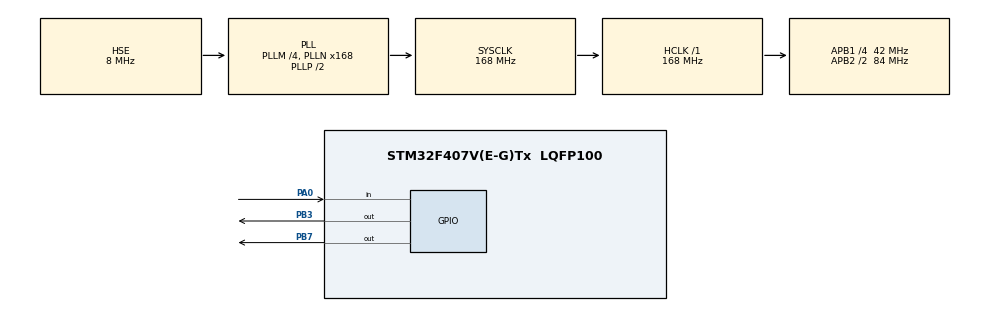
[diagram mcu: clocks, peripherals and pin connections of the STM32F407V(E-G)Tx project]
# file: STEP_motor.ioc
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Mcu.Family=STM32F4
Mcu.Name=STM32F407V(E-G)Tx
Mcu.Package=LQFP100
NVIC.PriorityGroup=NVIC_PRIORITYGROUP_4
PA0-WKUP.GPIO_PuPd=GPIO_PULLDOWN
PA0-WKUP.Signal=GPIO_Input
PA13.Mode=Serial_Wire
PA13.Signal=SYS_JTMS-SWDIO
PA14.Mode=Serial_Wire
PA14.Signal=SYS_JTCK-SWCLK
PB3.Signal=GPIO_Output
PB7.Signal=GPIO_Output
PH0-OSC_IN.Mode=HSE-External-Oscillator
PH0-OSC_IN.Signal=RCC_OSC_IN
PH1-OSC_OUT.Mode=HSE-External-Oscillator
PH1-OSC_OUT.Signal=RCC_OSC_OUT
ProjectManager.HeapSize=0x200
ProjectManager.StackSize=0x400
ProjectManager.TargetToolchain=MDK-ARM V5.27
RCC.48MHZClocksFreq_Value=84000000
RCC.AHBFreq_Value=168000000
RCC.APB1CLKDivider=RCC_HCLK_DIV4
RCC.APB1Freq_Value=42000000
RCC.APB1TimFreq_Value=84000000
RCC.APB2CLKDivider=RCC_HCLK_DIV2
RCC.APB2Freq_Value=84000000
RCC.APB2TimFreq_Value=168000000
RCC.CortexFreq_Value=168000000
RCC.HCLKFreq_Value=168000000
RCC.HSE_VALUE=8000000
RCC.HSI_VALUE=16000000
RCC.LSE_VALUE=32768
RCC.PLLM=4
RCC.PLLN=168
RCC.PLLSourceVirtual=RCC_PLLSOURCE_HSE
RCC.SYSCLKFreq_VALUE=168000000
RCC.SYSCLKSource=RCC_SYSCLKSOURCE_PLLCLK
RCC.VCOOutputFreq_Value=336000000
board=custom

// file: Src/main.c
/* USER CODE BEGIN Header */
/**
  ******************************************************************************
  * @file           : main.c
  * @brief          : Main program body
  ******************************************************************************
  * @attention
  *
  * <h2><center>&copy; Copyright (c) 2020 STMicroelectronics.
  * All rights reserved.</center></h2>
  *
  * This software component is licensed by ST under BSD 3-Clause license,
  * the "License"; You may not use this file except in compliance with the
  * License. You may obtain a copy of the License at:
  *                        opensource.org/licenses/BSD-3-Clause
  *
  ******************************************************************************
  */
/* USER CODE END Header */

#include "main.h"

void SystemClock_Config(void);
static void MX_GPIO_Init(void);

int main(void)
{

  /* MCU Configuration--------------------------------------------------------*/

  /* Reset of all peripherals, Initializes the Flash interface and the Systick. */
  HAL_Init();

  /* Configure the system clock */
  SystemClock_Config();

  /* Initialize all configured peripherals */
  MX_GPIO_Init();

  /* USER CODE END 2 */

  /* Infinite loop */
  while (1)
  {
		if(HAL_GPIO_ReadPin(GPIOA, GPIO_PIN_0))
		{

		    HAL_GPIO_WritePin(GPIOB, GPIO_PIN_7, GPIO_PIN_SET);  // Direction Pin

			HAL_GPIO_WritePin(GPIOB, GPIO_PIN_3, GPIO_PIN_SET);  // Step Pin
			HAL_Delay(50);
			HAL_GPIO_WritePin(GPIOB, GPIO_PIN_3, GPIO_PIN_RESET);
		}
		else
		{

			HAL_GPIO_WritePin(GPIOB, GPIO_PIN_7, GPIO_PIN_RESET);

			HAL_GPIO_WritePin(GPIOB, GPIO_PIN_3, GPIO_PIN_SET);
			HAL_Delay(50);
			HAL_GPIO_WritePin(GPIOB, GPIO_PIN_3, GPIO_PIN_RESET);
		}

  }
}

void SystemClock_Config(void)
{
  RCC_OscInitTypeDef RCC_OscInitStruct = {0};
  RCC_ClkInitTypeDef RCC_ClkInitStruct = {0};

  /** Configure the main internal regulator output voltage
  */
  __HAL_RCC_PWR_CLK_ENABLE();
  __HAL_PWR_VOLTAGESCALING_CONFIG(PWR_REGULATOR_VOLTAGE_SCALE1);
  /** Initializes the CPU, AHB and APB busses clocks
  */
  RCC_OscInitStruct.OscillatorType = RCC_OSCILLATORTYPE_HSE;
  RCC_OscInitStruct.HSEState = RCC_HSE_ON;
  RCC_OscInitStruct.PLL.PLLState = RCC_PLL_ON;
  RCC_OscInitStruct.PLL.PLLSource = RCC_PLLSOURCE_HSE;
  RCC_OscInitStruct.PLL.PLLM = 4;
  RCC_OscInitStruct.PLL.PLLN = 168;
  RCC_OscInitStruct.PLL.PLLP = RCC_PLLP_DIV2;
  RCC_OscInitStruct.PLL.PLLQ = 4;
  if (HAL_RCC_OscConfig(&RCC_OscInitStruct) != HAL_OK)
  {
    Error_Handler();
  }
  /** Initializes the CPU, AHB and APB busses clocks
  */
  RCC_ClkInitStruct.ClockType = RCC_CLOCKTYPE_HCLK|RCC_CLOCKTYPE_SYSCLK
                              |RCC_CLOCKTYPE_PCLK1|RCC_CLOCKTYPE_PCLK2;
  RCC_ClkInitStruct.SYSCLKSource = RCC_SYSCLKSOURCE_PLLCLK;
  RCC_ClkInitStruct.AHBCLKDivider = RCC_SYSCLK_DIV1;
  RCC_ClkInitStruct.APB1CLKDivider = RCC_HCLK_DIV4;
  RCC_ClkInitStruct.APB2CLKDivider = RCC_HCLK_DIV2;

  if (HAL_RCC_ClockConfig(&RCC_ClkInitStruct, FLASH_LATENCY_5) != HAL_OK)
  {
    Error_Handler();
  }
}

static void MX_GPIO_Init(void)
{
  GPIO_InitTypeDef GPIO_InitStruct = {0};

  /* GPIO Ports Clock Enable */
  __HAL_RCC_GPIOH_CLK_ENABLE();
  __HAL_RCC_GPIOA_CLK_ENABLE();
  __HAL_RCC_GPIOB_CLK_ENABLE();
  __HAL_RCC_GPIOD_CLK_ENABLE();

  /*Configure GPIO pin Output Level */
  HAL_GPIO_WritePin(GPIOA, E_Pin|RS_Pin, GPIO_PIN_RESET);

  /*Configure GPIO pin Output Level */
  HAL_GPIO_WritePin(GPIOB, D4_Pin|D5_Pin|D6_Pin|D7_Pin
                          |GPIO_PIN_3|GPIO_PIN_7, GPIO_PIN_RESET);

  /*Configure GPIO pin Output Level */
  HAL_GPIO_WritePin(GPIOD, D0_Pin|D1_Pin|D2_Pin|D3_Pin, GPIO_PIN_RESET);

  /*Configure GPIO pin : PA0 */
  GPIO_InitStruct.Pin = GPIO_PIN_0;
  GPIO_InitStruct.Mode = GPIO_MODE_INPUT;
  GPIO_InitStruct.Pull = GPIO_PULLDOWN;
  HAL_GPIO_Init(GPIOA, &GPIO_InitStruct);

  /*Configure GPIO pins : E_Pin RS_Pin */
  GPIO_InitStruct.Pin = E_Pin|RS_Pin;
  GPIO_InitStruct.Mode = GPIO_MODE_OUTPUT_PP;
  GPIO_InitStruct.Pull = GPIO_NOPULL;
  GPIO_InitStruct.Speed = GPIO_SPEED_FREQ_LOW;
  HAL_GPIO_Init(GPIOA, &GPIO_InitStruct);

  /*Configure GPIO pins : D4_Pin D5_Pin D6_Pin D7_Pin
                           PB3 PB7 */
  GPIO_InitStruct.Pin = D4_Pin|D5_Pin|D6_Pin|D7_Pin
                          |GPIO_PIN_3|GPIO_PIN_7;
  GPIO_InitStruct.Mode = GPIO_MODE_OUTPUT_PP;
  GPIO_InitStruct.Pull = GPIO_NOPULL;
  GPIO_InitStruct.Speed = GPIO_SPEED_FREQ_LOW;
  HAL_GPIO_Init(GPIOB, &GPIO_InitStruct);

  /*Configure GPIO pins : D0_Pin D1_Pin D2_Pin D3_Pin */
  GPIO_InitStruct.Pin = D0_Pin|D1_Pin|D2_Pin|D3_Pin;
  GPIO_InitStruct.Mode = GPIO_MODE_OUTPUT_PP;
  GPIO_InitStruct.Pull = GPIO_NOPULL;
  GPIO_InitStruct.Speed = GPIO_SPEED_FREQ_LOW;
  HAL_GPIO_Init(GPIOD, &GPIO_InitStruct);

}

void Error_Handler(void)
{
}

/************************ (C) COPYRIGHT STMicroelectronics *****END OF FILE****/
